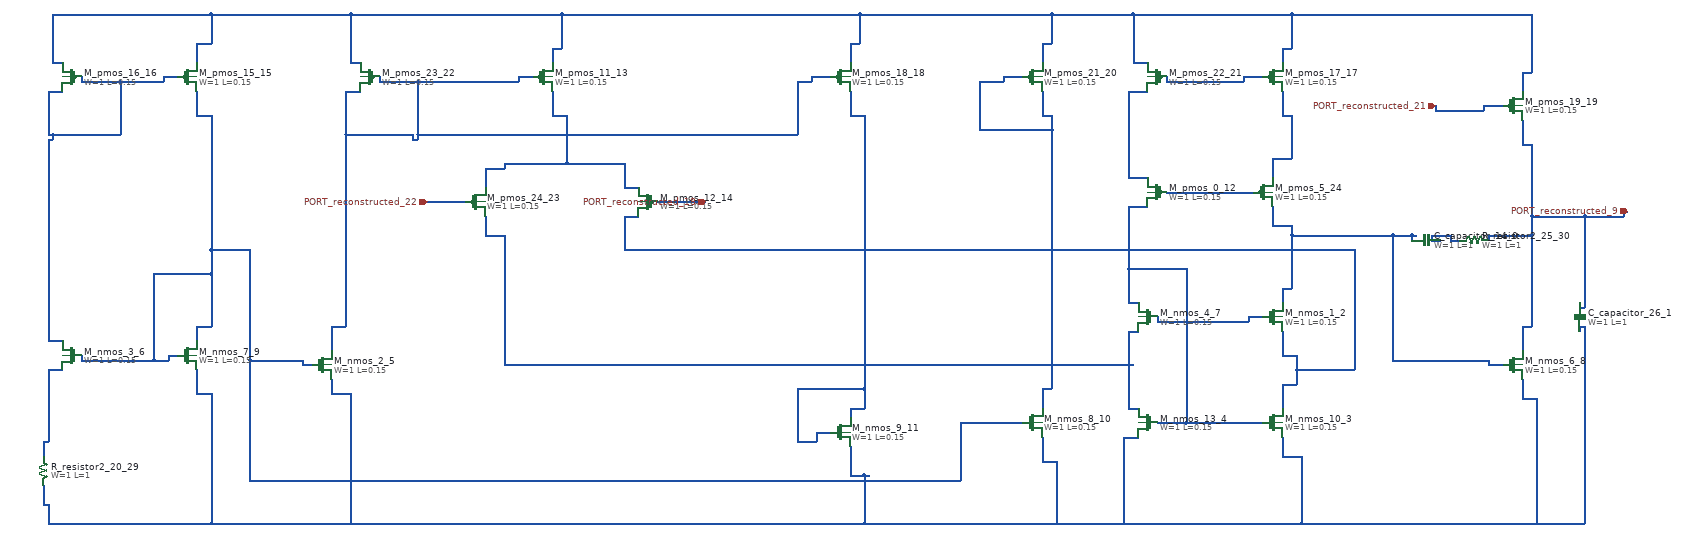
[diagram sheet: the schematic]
v {xschem version=3.4.8 file_version=1.2}
G {}
K {}
V {}
S {}
E {}
C {sky130_fd_pr/cap_mim_m3_1.sym} 3020 580 1 0 {name="C_capacitor_14_0" model=cap_mim_m3_1 W=1 L=1 MF=1 spiceprefix=X}
C {sky130_fd_pr/cap_mim_m3_1.sym} 3340 740 2 0 {name="C_capacitor_26_1" model=cap_mim_m3_1 W=1 L=1 MF=1 spiceprefix=X}
C {sky130_fd_pr/nfet3_01v8.sym} 2700 740 0 0 {name="M_nmos_1_2"
W=1
L=0.15
body=GND
nf=1
mult=1
ad="expr('int((@nf + 1)/2) * @W / @nf * 0.29')"
pd="expr('2*int((@nf + 1)/2) * (@W / @nf + 0.29)')"
as="expr('int((@nf + 2)/2) * @W / @nf * 0.29')"
ps="expr('2*int((@nf + 2)/2) * (@W / @nf + 0.29)')"
nrd="expr('0.29 / @W ')" nrs="expr('0.29 / @W ')"
sa=0 sb=0 sd=0
model=nfet_01v8
spiceprefix=X
}
C {sky130_fd_pr/nfet3_01v8.sym} 2700 960 0 0 {name="M_nmos_10_3"
W=1
L=0.15
body=GND
nf=1
mult=1
ad="expr('int((@nf + 1)/2) * @W / @nf * 0.29')"
pd="expr('2*int((@nf + 1)/2) * (@W / @nf + 0.29)')"
as="expr('int((@nf + 2)/2) * @W / @nf * 0.29')"
ps="expr('2*int((@nf + 2)/2) * (@W / @nf + 0.29)')"
nrd="expr('0.29 / @W ')" nrs="expr('0.29 / @W ')"
sa=0 sb=0 sd=0
model=nfet_01v8
spiceprefix=X
}
C {sky130_fd_pr/nfet3_01v8.sym} 2440 960 0 1 {name="M_nmos_13_4"
W=1
L=0.15
body=GND
nf=1
mult=1
ad="expr('int((@nf + 1)/2) * @W / @nf * 0.29')"
pd="expr('2*int((@nf + 1)/2) * (@W / @nf + 0.29)')"
as="expr('int((@nf + 2)/2) * @W / @nf * 0.29')"
ps="expr('2*int((@nf + 2)/2) * (@W / @nf + 0.29)')"
nrd="expr('0.29 / @W ')" nrs="expr('0.29 / @W ')"
sa=0 sb=0 sd=0
model=nfet_01v8
spiceprefix=X
}
C {sky130_fd_pr/nfet3_01v8.sym} 720 840 0 0 {name="M_nmos_2_5"
W=1
L=0.15
body=GND
nf=1
mult=1
ad="expr('int((@nf + 1)/2) * @W / @nf * 0.29')"
pd="expr('2*int((@nf + 1)/2) * (@W / @nf + 0.29)')"
as="expr('int((@nf + 2)/2) * @W / @nf * 0.29')"
ps="expr('2*int((@nf + 2)/2) * (@W / @nf + 0.29)')"
nrd="expr('0.29 / @W ')" nrs="expr('0.29 / @W ')"
sa=0 sb=0 sd=0
model=nfet_01v8
spiceprefix=X
}
C {sky130_fd_pr/nfet3_01v8.sym} 200 820 0 1 {name="M_nmos_3_6"
W=1
L=0.15
body=GND
nf=1
mult=1
ad="expr('int((@nf + 1)/2) * @W / @nf * 0.29')"
pd="expr('2*int((@nf + 1)/2) * (@W / @nf + 0.29)')"
as="expr('int((@nf + 2)/2) * @W / @nf * 0.29')"
ps="expr('2*int((@nf + 2)/2) * (@W / @nf + 0.29)')"
nrd="expr('0.29 / @W ')" nrs="expr('0.29 / @W ')"
sa=0 sb=0 sd=0
model=nfet_01v8
spiceprefix=X
}
C {sky130_fd_pr/nfet3_01v8.sym} 2440 740 0 1 {name="M_nmos_4_7"
W=1
L=0.15
body=GND
nf=1
mult=1
ad="expr('int((@nf + 1)/2) * @W / @nf * 0.29')"
pd="expr('2*int((@nf + 1)/2) * (@W / @nf + 0.29)')"
as="expr('int((@nf + 2)/2) * @W / @nf * 0.29')"
ps="expr('2*int((@nf + 2)/2) * (@W / @nf + 0.29)')"
nrd="expr('0.29 / @W ')" nrs="expr('0.29 / @W ')"
sa=0 sb=0 sd=0
model=nfet_01v8
spiceprefix=X
}
C {sky130_fd_pr/nfet3_01v8.sym} 3200 840 0 0 {name="M_nmos_6_8"
W=1
L=0.15
body=GND
nf=1
mult=1
ad="expr('int((@nf + 1)/2) * @W / @nf * 0.29')"
pd="expr('2*int((@nf + 1)/2) * (@W / @nf + 0.29)')"
as="expr('int((@nf + 2)/2) * @W / @nf * 0.29')"
ps="expr('2*int((@nf + 2)/2) * (@W / @nf + 0.29)')"
nrd="expr('0.29 / @W ')" nrs="expr('0.29 / @W ')"
sa=0 sb=0 sd=0
model=nfet_01v8
spiceprefix=X
}
C {sky130_fd_pr/nfet3_01v8.sym} 440 820 0 0 {name="M_nmos_7_9"
W=1
L=0.15
body=GND
nf=1
mult=1
ad="expr('int((@nf + 1)/2) * @W / @nf * 0.29')"
pd="expr('2*int((@nf + 1)/2) * (@W / @nf + 0.29)')"
as="expr('int((@nf + 2)/2) * @W / @nf * 0.29')"
ps="expr('2*int((@nf + 2)/2) * (@W / @nf + 0.29)')"
nrd="expr('0.29 / @W ')" nrs="expr('0.29 / @W ')"
sa=0 sb=0 sd=0
model=nfet_01v8
spiceprefix=X
}
C {sky130_fd_pr/nfet3_01v8.sym} 2200 960 0 0 {name="M_nmos_8_10"
W=1
L=0.15
body=GND
nf=1
mult=1
ad="expr('int((@nf + 1)/2) * @W / @nf * 0.29')"
pd="expr('2*int((@nf + 1)/2) * (@W / @nf + 0.29)')"
as="expr('int((@nf + 2)/2) * @W / @nf * 0.29')"
ps="expr('2*int((@nf + 2)/2) * (@W / @nf + 0.29)')"
nrd="expr('0.29 / @W ')" nrs="expr('0.29 / @W ')"
sa=0 sb=0 sd=0
model=nfet_01v8
spiceprefix=X
}
C {sky130_fd_pr/nfet3_01v8.sym} 1800 980 0 0 {name="M_nmos_9_11"
W=1
L=0.15
body=GND
nf=1
mult=1
ad="expr('int((@nf + 1)/2) * @W / @nf * 0.29')"
pd="expr('2*int((@nf + 1)/2) * (@W / @nf + 0.29)')"
as="expr('int((@nf + 2)/2) * @W / @nf * 0.29')"
ps="expr('2*int((@nf + 2)/2) * (@W / @nf + 0.29)')"
nrd="expr('0.29 / @W ')" nrs="expr('0.29 / @W ')"
sa=0 sb=0 sd=0
model=nfet_01v8
spiceprefix=X
}
C {sky130_fd_pr/pfet3_01v8.sym} 2460 480 0 1 {name="M_pmos_0_12"
W=1
L=0.15
body=VDD
nf=1
mult=1
ad="expr('int((@nf + 1)/2) * @W / @nf * 0.29')"
pd="expr('2*int((@nf + 1)/2) * (@W / @nf + 0.29)')"
as="expr('int((@nf + 2)/2) * @W / @nf * 0.29')"
ps="expr('2*int((@nf + 2)/2) * (@W / @nf + 0.29)')"
nrd="expr('0.29 / @W ')" nrs="expr('0.29 / @W ')"
sa=0 sb=0 sd=0
model=pfet_01v8
spiceprefix=X
}
C {sky130_fd_pr/pfet3_01v8.sym} 1180 240 0 0 {name="M_pmos_11_13"
W=1
L=0.15
body=VDD
nf=1
mult=1
ad="expr('int((@nf + 1)/2) * @W / @nf * 0.29')"
pd="expr('2*int((@nf + 1)/2) * (@W / @nf + 0.29)')"
as="expr('int((@nf + 2)/2) * @W / @nf * 0.29')"
ps="expr('2*int((@nf + 2)/2) * (@W / @nf + 0.29)')"
nrd="expr('0.29 / @W ')" nrs="expr('0.29 / @W ')"
sa=0 sb=0 sd=0
model=pfet_01v8
spiceprefix=X
}
C {sky130_fd_pr/pfet3_01v8.sym} 1400 500 0 1 {name="M_pmos_12_14"
W=1
L=0.15
body=VDD
nf=1
mult=1
ad="expr('int((@nf + 1)/2) * @W / @nf * 0.29')"
pd="expr('2*int((@nf + 1)/2) * (@W / @nf + 0.29)')"
as="expr('int((@nf + 2)/2) * @W / @nf * 0.29')"
ps="expr('2*int((@nf + 2)/2) * (@W / @nf + 0.29)')"
nrd="expr('0.29 / @W ')" nrs="expr('0.29 / @W ')"
sa=0 sb=0 sd=0
model=pfet_01v8
spiceprefix=X
}
C {sky130_fd_pr/pfet3_01v8.sym} 440 240 0 0 {name="M_pmos_15_15"
W=1
L=0.15
body=VDD
nf=1
mult=1
ad="expr('int((@nf + 1)/2) * @W / @nf * 0.29')"
pd="expr('2*int((@nf + 1)/2) * (@W / @nf + 0.29)')"
as="expr('int((@nf + 2)/2) * @W / @nf * 0.29')"
ps="expr('2*int((@nf + 2)/2) * (@W / @nf + 0.29)')"
nrd="expr('0.29 / @W ')" nrs="expr('0.29 / @W ')"
sa=0 sb=0 sd=0
model=pfet_01v8
spiceprefix=X
}
C {sky130_fd_pr/pfet3_01v8.sym} 200 240 0 1 {name="M_pmos_16_16"
W=1
L=0.15
body=VDD
nf=1
mult=1
ad="expr('int((@nf + 1)/2) * @W / @nf * 0.29')"
pd="expr('2*int((@nf + 1)/2) * (@W / @nf + 0.29)')"
as="expr('int((@nf + 2)/2) * @W / @nf * 0.29')"
ps="expr('2*int((@nf + 2)/2) * (@W / @nf + 0.29)')"
nrd="expr('0.29 / @W ')" nrs="expr('0.29 / @W ')"
sa=0 sb=0 sd=0
model=pfet_01v8
spiceprefix=X
}
C {sky130_fd_pr/pfet3_01v8.sym} 2700 240 0 0 {name="M_pmos_17_17"
W=1
L=0.15
body=VDD
nf=1
mult=1
ad="expr('int((@nf + 1)/2) * @W / @nf * 0.29')"
pd="expr('2*int((@nf + 1)/2) * (@W / @nf + 0.29)')"
as="expr('int((@nf + 2)/2) * @W / @nf * 0.29')"
ps="expr('2*int((@nf + 2)/2) * (@W / @nf + 0.29)')"
nrd="expr('0.29 / @W ')" nrs="expr('0.29 / @W ')"
sa=0 sb=0 sd=0
model=pfet_01v8
spiceprefix=X
}
C {sky130_fd_pr/pfet3_01v8.sym} 1800 240 0 0 {name="M_pmos_18_18"
W=1
L=0.15
body=VDD
nf=1
mult=1
ad="expr('int((@nf + 1)/2) * @W / @nf * 0.29')"
pd="expr('2*int((@nf + 1)/2) * (@W / @nf + 0.29)')"
as="expr('int((@nf + 2)/2) * @W / @nf * 0.29')"
ps="expr('2*int((@nf + 2)/2) * (@W / @nf + 0.29)')"
nrd="expr('0.29 / @W ')" nrs="expr('0.29 / @W ')"
sa=0 sb=0 sd=0
model=pfet_01v8
spiceprefix=X
}
C {sky130_fd_pr/pfet3_01v8.sym} 3200 300 0 0 {name="M_pmos_19_19"
W=1
L=0.15
body=VDD
nf=1
mult=1
ad="expr('int((@nf + 1)/2) * @W / @nf * 0.29')"
pd="expr('2*int((@nf + 1)/2) * (@W / @nf + 0.29)')"
as="expr('int((@nf + 2)/2) * @W / @nf * 0.29')"
ps="expr('2*int((@nf + 2)/2) * (@W / @nf + 0.29)')"
nrd="expr('0.29 / @W ')" nrs="expr('0.29 / @W ')"
sa=0 sb=0 sd=0
model=pfet_01v8
spiceprefix=X
}
C {sky130_fd_pr/pfet3_01v8.sym} 2200 240 0 0 {name="M_pmos_21_20"
W=1
L=0.15
body=VDD
nf=1
mult=1
ad="expr('int((@nf + 1)/2) * @W / @nf * 0.29')"
pd="expr('2*int((@nf + 1)/2) * (@W / @nf + 0.29)')"
as="expr('int((@nf + 2)/2) * @W / @nf * 0.29')"
ps="expr('2*int((@nf + 2)/2) * (@W / @nf + 0.29)')"
nrd="expr('0.29 / @W ')" nrs="expr('0.29 / @W ')"
sa=0 sb=0 sd=0
model=pfet_01v8
spiceprefix=X
}
C {sky130_fd_pr/pfet3_01v8.sym} 2460 240 0 1 {name="M_pmos_22_21"
W=1
L=0.15
body=VDD
nf=1
mult=1
ad="expr('int((@nf + 1)/2) * @W / @nf * 0.29')"
pd="expr('2*int((@nf + 1)/2) * (@W / @nf + 0.29)')"
as="expr('int((@nf + 2)/2) * @W / @nf * 0.29')"
ps="expr('2*int((@nf + 2)/2) * (@W / @nf + 0.29)')"
nrd="expr('0.29 / @W ')" nrs="expr('0.29 / @W ')"
sa=0 sb=0 sd=0
model=pfet_01v8
spiceprefix=X
}
C {sky130_fd_pr/pfet3_01v8.sym} 820 240 0 1 {name="M_pmos_23_22"
W=1
L=0.15
body=VDD
nf=1
mult=1
ad="expr('int((@nf + 1)/2) * @W / @nf * 0.29')"
pd="expr('2*int((@nf + 1)/2) * (@W / @nf + 0.29)')"
as="expr('int((@nf + 2)/2) * @W / @nf * 0.29')"
ps="expr('2*int((@nf + 2)/2) * (@W / @nf + 0.29)')"
nrd="expr('0.29 / @W ')" nrs="expr('0.29 / @W ')"
sa=0 sb=0 sd=0
model=pfet_01v8
spiceprefix=X
}
C {sky130_fd_pr/pfet3_01v8.sym} 1040 500 0 0 {name="M_pmos_24_23"
W=1
L=0.15
body=VDD
nf=1
mult=1
ad="expr('int((@nf + 1)/2) * @W / @nf * 0.29')"
pd="expr('2*int((@nf + 1)/2) * (@W / @nf + 0.29)')"
as="expr('int((@nf + 2)/2) * @W / @nf * 0.29')"
ps="expr('2*int((@nf + 2)/2) * (@W / @nf + 0.29)')"
nrd="expr('0.29 / @W ')" nrs="expr('0.29 / @W ')"
sa=0 sb=0 sd=0
model=pfet_01v8
spiceprefix=X
}
C {sky130_fd_pr/pfet3_01v8.sym} 2680 480 0 0 {name="M_pmos_5_24"
W=1
L=0.15
body=VDD
nf=1
mult=1
ad="expr('int((@nf + 1)/2) * @W / @nf * 0.29')"
pd="expr('2*int((@nf + 1)/2) * (@W / @nf + 0.29)')"
as="expr('int((@nf + 2)/2) * @W / @nf * 0.29')"
ps="expr('2*int((@nf + 2)/2) * (@W / @nf + 0.29)')"
nrd="expr('0.29 / @W ')" nrs="expr('0.29 / @W ')"
sa=0 sb=0 sd=0
model=pfet_01v8
spiceprefix=X
}
C {devices/ipin.sym} 3440 520 0 0 {name="p_port_27_25" lab="PORT_reconstructed_9"}
C {devices/ipin.sym} 940 500 0 0 {name="p_port_28_26" lab="PORT_reconstructed_22"}
C {devices/ipin.sym} 1520 500 0 0 {name="p_port_29_27" lab="PORT_reconstructed_18"}
C {devices/ipin.sym} 3040 300 0 0 {name="p_port_33_28" lab="PORT_reconstructed_21"}
C {sky130_fd_pr/res_generic_po.sym} 140 1060 0 0 {name="R_resistor2_20_29"
W=1
L=1
model=res_generic_po
spiceprefix=X
mult=1}
C {sky130_fd_pr/res_generic_po.sym} 3120 580 3 0 {name="R_resistor2_25_30"
W=1
L=1
model=res_generic_po
spiceprefix=X
mult=1}
N 3150 840 3180 840 {}
N 2950 830 3150 830 {}
N 2720 680 2740 680 {}
N 2740 570 2950 570 {}
N 2950 570 2990 570 {}
N 2990 570 3000 570 {}
N 2700 550 2740 550 {}
N 2700 550 2700 510 {}
N 2720 710 2720 680 {}
N 2740 680 2740 570 {}
N 2740 570 2740 550 {}
N 2950 830 2950 570 {}
N 2990 580 2990 570 {}
N 3150 840 3150 830 {}
N 3030 580 3050 580 {}
N 3070 580 3090 580 {}
N 3030 570 3070 570 {}
N 3030 580 3030 570 {}
N 3070 580 3070 570 {}
N 2460 750 2650 750 {}
N 2650 740 2680 740 {}
N 2460 750 2460 740 {}
N 2650 750 2650 740 {}
N 2220 890 2240 890 {}
N 2090 350 2240 350 {}
N 2220 320 2240 320 {}
N 2090 250 2140 250 {}
N 2140 240 2180 240 {}
N 2090 350 2090 250 {}
N 2140 250 2140 240 {}
N 2220 930 2220 890 {}
N 2220 320 2220 270 {}
N 2240 890 2240 350 {}
N 2240 350 2240 320 {}
N 1710 1000 1750 1000 {}
N 1750 980 1780 980 {}
N 1820 930 1850 930 {}
N 1710 890 1850 890 {}
N 1820 320 1850 320 {}
N 1710 1000 1710 890 {}
N 1750 1000 1750 980 {}
N 1820 950 1820 930 {}
N 1820 320 1820 270 {}
N 1850 930 1850 890 {}
N 1850 890 1850 320 {}
N 2400 450 2440 450 {}
N 2400 270 2440 270 {}
N 2400 450 2400 270 {}
N 2480 480 2660 480 {}
N 3220 230 3240 230 {}
N 160 210 180 210 {}
N 780 210 800 210 {}
N 2410 210 2440 210 {}
N 1200 180 1220 180 {}
N 2720 180 2740 180 {}
N 460 170 490 170 {}
N 1820 170 1840 170 {}
N 2220 170 2240 170 {}
N 160 110 490 110 {}
N 490 110 780 110 {}
N 780 110 1220 110 {}
N 1220 110 1840 110 {}
N 1840 110 2240 110 {}
N 2240 110 2410 110 {}
N 2410 110 2740 110 {}
N 2740 110 3240 110 {}
N 160 210 160 110 {}
N 460 210 460 170 {}
N 490 170 490 110 {}
N 780 210 780 110 {}
N 1200 210 1200 180 {}
N 1220 180 1220 110 {}
N 1820 210 1820 170 {}
N 1840 170 1840 110 {}
N 2220 210 2220 170 {}
N 2240 170 2240 110 {}
N 2410 210 2410 110 {}
N 2720 210 2720 180 {}
N 2740 180 2740 110 {}
N 3220 270 3220 230 {}
N 3240 230 3240 110 {}
N 1350 470 1380 470 {}
N 1060 430 1100 430 {}
N 1100 420 1230 420 {}
N 1230 420 1350 420 {}
N 1200 320 1230 320 {}
N 1060 470 1060 430 {}
N 1100 430 1100 420 {}
N 1200 320 1200 270 {}
N 1230 420 1230 320 {}
N 1350 470 1350 420 {}
N 2720 880 2750 880 {}
N 2750 850 2870 850 {}
N 2720 820 2750 820 {}
N 1350 600 2870 600 {}
N 1350 530 1380 530 {}
N 1350 600 1350 530 {}
N 2720 930 2720 880 {}
N 2720 820 2720 770 {}
N 2750 880 2750 850 {}
N 2750 850 2750 820 {}
N 2870 850 2870 600 {}
N 1420 500 1520 500 {}
N 2700 410 2740 410 {}
N 2720 320 2740 320 {}
N 2700 450 2700 410 {}
N 2720 320 2720 270 {}
N 2740 410 2740 320 {}
N 150 1170 490 1170 {}
N 490 1170 780 1170 {}
N 780 1170 1850 1170 {}
N 1850 1170 2250 1170 {}
N 2250 1170 2390 1170 {}
N 2390 1170 2760 1170 {}
N 2760 1170 3250 1170 {}
N 3250 1170 3350 1170 {}
N 140 1130 150 1130 {}
N 1820 1070 1850 1070 {}
N 1850 1070 1860 1070 {}
N 2220 1040 2250 1040 {}
N 2720 1030 2760 1030 {}
N 2390 990 2420 990 {}
N 3220 910 3250 910 {}
N 460 900 490 900 {}
N 740 900 780 900 {}
N 3340 760 3350 760 {}
N 140 1130 140 1090 {}
N 150 1170 150 1130 {}
N 460 900 460 850 {}
N 490 1170 490 900 {}
N 740 900 740 870 {}
N 780 1170 780 900 {}
N 1820 1070 1820 1010 {}
N 1850 1170 1850 1070 {}
N 2220 1040 2220 990 {}
N 2250 1170 2250 1040 {}
N 2390 1170 2390 990 {}
N 2720 1030 2720 990 {}
N 2760 1170 2760 1030 {}
N 3220 910 3220 870 {}
N 3250 1170 3250 910 {}
N 3340 770 3340 760 {}
N 3350 1170 3350 760 {}
N 2480 250 2640 250 {}
N 2640 240 2680 240 {}
N 2480 250 2480 240 {}
N 2640 250 2640 240 {}
N 3040 310 3140 310 {}
N 3140 300 3180 300 {}
N 3040 310 3040 300 {}
N 3140 310 3140 300 {}
N 940 500 1020 500 {}
N 2400 930 2420 930 {}
N 1100 840 2400 840 {}
N 2400 840 2410 840 {}
N 2400 770 2420 770 {}
N 1060 570 1100 570 {}
N 1060 570 1060 530 {}
N 1100 840 1100 570 {}
N 2400 930 2400 840 {}
N 2400 840 2400 770 {}
N 2460 960 2520 960 {}
N 2520 960 2680 960 {}
N 2400 710 2420 710 {}
N 2400 640 2520 640 {}
N 2400 510 2440 510 {}
N 2400 710 2400 640 {}
N 2400 640 2400 510 {}
N 2520 960 2520 640 {}
N 740 760 770 760 {}
N 910 370 920 370 {}
N 770 360 910 360 {}
N 920 360 1710 360 {}
N 770 270 800 270 {}
N 840 250 920 250 {}
N 920 250 1130 250 {}
N 1710 250 1740 250 {}
N 1130 240 1160 240 {}
N 1740 240 1780 240 {}
N 740 810 740 760 {}
N 770 760 770 360 {}
N 770 360 770 270 {}
N 840 250 840 240 {}
N 910 370 910 360 {}
N 920 370 920 360 {}
N 920 360 920 250 {}
N 1130 250 1130 240 {}
N 1710 360 1710 250 {}
N 1740 250 1740 240 {}
N 570 1080 2050 1080 {}
N 2050 960 2180 960 {}
N 680 840 700 840 {}
N 220 830 370 830 {}
N 370 830 400 830 {}
N 570 830 680 830 {}
N 400 820 420 820 {}
N 460 760 490 760 {}
N 370 650 490 650 {}
N 490 600 570 600 {}
N 460 320 490 320 {}
N 220 830 220 820 {}
N 370 830 370 650 {}
N 400 830 400 820 {}
N 460 790 460 760 {}
N 460 320 460 270 {}
N 490 760 490 650 {}
N 490 650 490 600 {}
N 490 600 490 320 {}
N 570 1080 570 830 {}
N 570 830 570 600 {}
N 680 840 680 830 {}
N 2050 1080 2050 960 {}
N 140 1000 150 1000 {}
N 150 850 180 850 {}
N 140 1030 140 1000 {}
N 150 1000 150 850 {}
N 150 790 180 790 {}
N 150 370 160 370 {}
N 150 360 160 360 {}
N 160 360 300 360 {}
N 150 270 180 270 {}
N 220 250 300 250 {}
N 300 250 390 250 {}
N 390 240 420 240 {}
N 150 790 150 370 {}
N 150 360 150 270 {}
N 160 370 160 360 {}
N 220 250 220 240 {}
N 300 360 300 250 {}
N 390 250 390 240 {}
N 3220 760 3240 760 {}
N 3340 720 3350 720 {}
N 3150 570 3240 570 {}
N 3240 530 3350 530 {}
N 3350 530 3430 530 {}
N 3430 520 3440 520 {}
N 3220 380 3240 380 {}
N 3150 580 3150 570 {}
N 3220 810 3220 760 {}
N 3220 380 3220 330 {}
N 3240 760 3240 570 {}
N 3240 570 3240 530 {}
N 3240 530 3240 380 {}
N 3340 720 3340 710 {}
N 3350 720 3350 530 {}
N 3430 530 3430 520 {}
